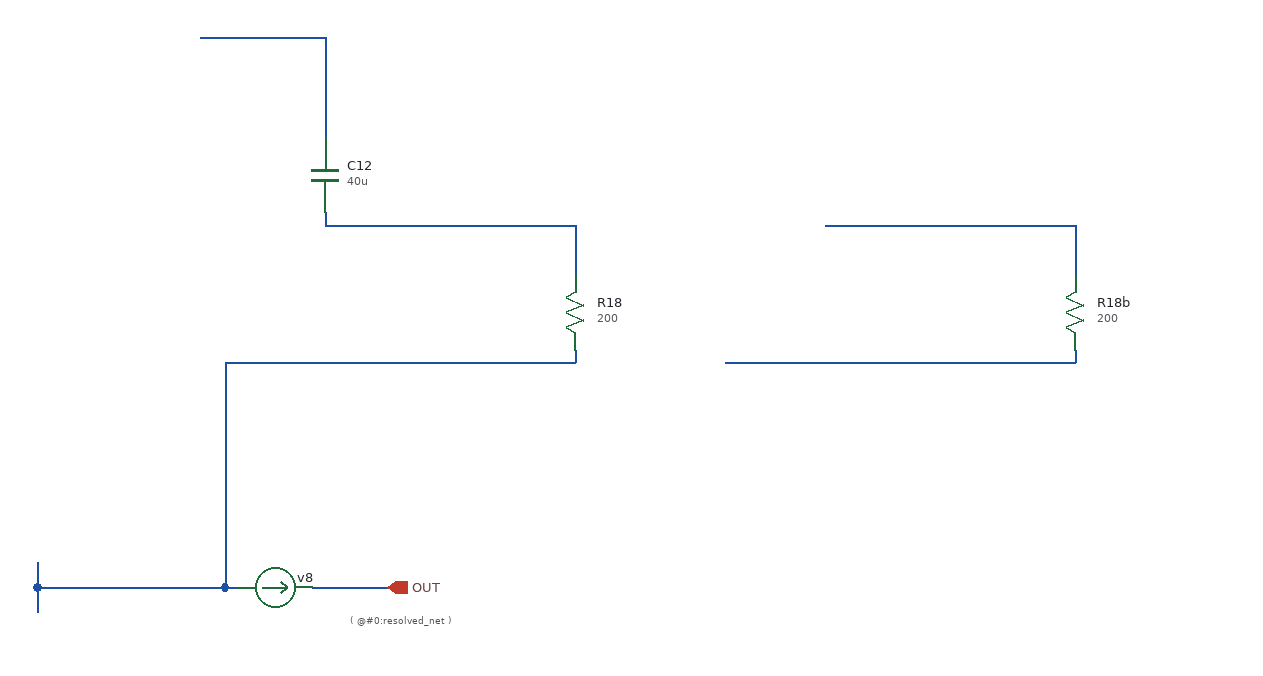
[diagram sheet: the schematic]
v {xschem version=3.4.8RC file_version=1.3}
G {}
K {}
V {}
S {}
F {}
E {}
T {( @#0:resolved_net )} -300 155 0 1 0.2 0.2 {name=p5 layer=15}
N -550 140 -550 160 {lab=#net1}
N -550 120 -550 140 {lab=#net1}
N -330 140 -270 140 {lab=OUT}
N -550 140 -400 140 {lab=#net1}
N -400 140 -390 140 {lab=#net1}
N -400 -40 -400 140 {lab=#net1}
N -120 -150 -120 -110 {lab=#net2}
N -320 -300 -320 -220 {lab=#net3}
N -420 -300 -320 -300 {lab=#net3}
N -320 -160 -320 -150 {lab=#net2}
N -320 -150 -120 -150 {lab=#net2}
N -400 -40 -120 -40 {lab=#net1}
N -120 -50 -120 -40 {lab=#net1}
N 280 -150 280 -110 {lab=#net4}
N 80 -150 280 -150 {lab=#net4}
N 0 -40 280 -40 {lab=#net5}
N 280 -50 280 -40 {lab=#net5}
C {devices/capa} -320 -190 0 0 {name=C12 m=1 value="40u"}
C {devices/res} -120 -80 0 1 {name=R18 m=1 value=200}
C {devices/res} 280 -80 0 1 {name=R18b m=1 value=200}
C {devices/ammeter} -360 140 3 0 {name=v8}
C {devices/opin} -270 140 0 0 {name=p5 lab=OUT}
